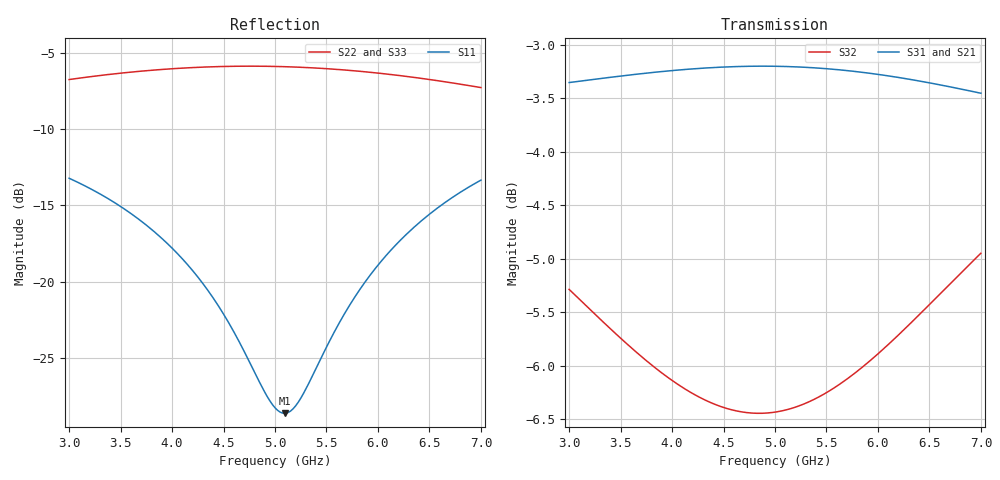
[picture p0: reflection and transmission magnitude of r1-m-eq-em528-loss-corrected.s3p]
! yapnr Order 0 prediction r1-m-eq-em528: predictions/references/r1-m-eq-em528/coarse_dense.s3p, loss-corrected
! substrate M-eq-em528; coupon model OSHPARK-4L-EM528; correction: path [('arm', 9.2), ('line', 6.0)]
! |S21|, |S31| (and S12, S13) scaled, phases kept; 50 ohm, e^(+jwt)
# GHz S RI R 50
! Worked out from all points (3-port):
!   161 points, 3 GHz to 7 GHz, reference 50 ohm
!   strongest paths, dB at 3 GHz, 4 GHz, 5 GHz, 6 GHz, 7 GHz:
!     S31: -3.4, -3.2, -3.2, -3.3, -3.5
!     S21: -3.4, -3.2, -3.2, -3.3, -3.5
!     S32: -5.3, -6.1, -6.4, -5.9, -4.9
!   lowest |S11| = -28.6 dB at 5.1 GHz (marker M1), VSWR 1.08, Z = 46.4 - j0.176 ohm
!   |S11| at or under -10 dB: start of sweep to end of sweep
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3  -0.1651 0.1429  0.00439 -0.6796  0.00439 -0.6796
   0.00442 -0.6796  -0.2416 0.3911  0.085 -0.5375
   0.00442 -0.6796  0.085 -0.5375  -0.2416 0.3911
3.55  -0.116 0.1269  -0.1952 -0.6564  -0.1952 -0.6564
      -0.1951 -0.6565  -0.1344 0.4653  -0.0268 -0.513
      -0.1951 -0.6565  -0.0268 -0.513  -0.1344 0.4653
4.125  -0.0722 0.0913  -0.3901 -0.5681  -0.3901 -0.5681
       -0.3901 -0.5683  0.00972 0.5015  -0.1187 -0.4743
       -0.3901 -0.5683  -0.1187 -0.4743  0.00972 0.5015
4.5  -0.0515 0.0591  -0.4992 -0.4777  -0.4992 -0.4777
     -0.4992 -0.4779  0.1113 0.495  -0.1685 -0.4486
     -0.4992 -0.4779  -0.1685 -0.4486  0.1113 0.495
5  -0.0377 0.00872  -0.6108 -0.3241  -0.6108 -0.3241
   -0.6109 -0.3243  0.2405 0.4468  -0.2305 -0.4174
   -0.6109 -0.3243  -0.2305 -0.4174  0.2405 0.4468
5.1  -0.037 -0.00189  -0.6277 -0.2898  -0.6277 -0.2898
     -0.6278 -0.29  0.2641 0.4322  -0.2431 -0.4114
     -0.6278 -0.29  -0.2431 -0.4114  0.2641 0.4322
5.25  -0.0375 -0.0179  -0.6491 -0.2367  -0.6491 -0.2367
      -0.6492 -0.2369  0.2973 0.4073  -0.2624 -0.4024
      -0.6492 -0.2369  -0.2624 -0.4024  0.2973 0.4073
5.675  -0.0479 -0.0623  -0.6839 -0.079  -0.6839 -0.079
       -0.6841 -0.0791  0.3748 0.322  -0.3208 -0.3745
       -0.6841 -0.0791  -0.3208 -0.3745  0.3748 0.322
6.025  -0.0661 -0.0954  -0.6831 0.0532  -0.6831 0.0532
       -0.6833 0.0531  0.4173 0.2406  -0.3739 -0.3453
       -0.6833 0.0531  -0.3739 -0.3453  0.4173 0.2406
7  -0.1506 -0.1538  -0.5512 0.384  -0.5512 0.384
   -0.5514 0.384  0.4324 0.014  -0.5279 -0.2032
   -0.5514 0.384  -0.5279 -0.2032  0.4324 0.014
